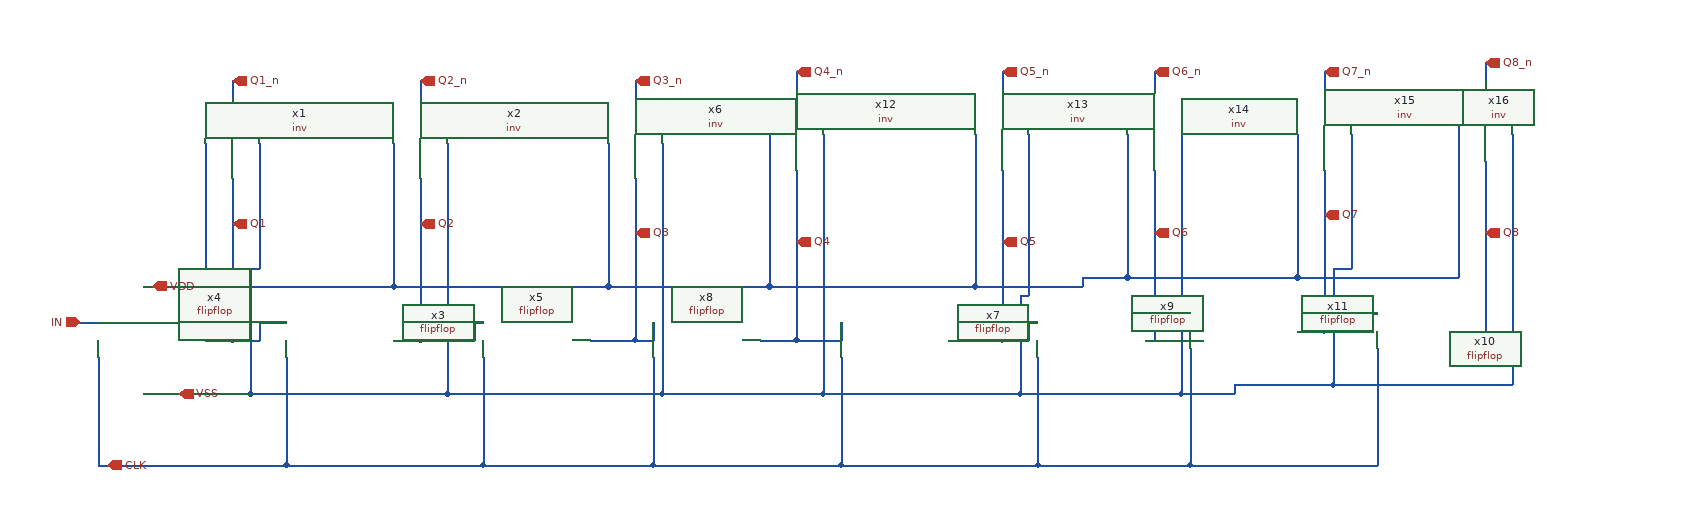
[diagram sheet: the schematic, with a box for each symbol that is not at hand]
v {xschem version=3.4.6 file_version=1.2}
G {}
K {}
V {}
S {}
E {}
N -20 -0 10 -0 {lab=Q1}
N 10 -20 10 -0 {lab=Q1}
N 10 -20 40 -20 {lab=Q1}
N 810 -60 930 -60 {lab=VDD}
N 1040 60 1100 60 {lab=VSS}
N 190 -0 250 0 {lab=Q2}
N 250 -20 250 0 {lab=Q2}
N 250 -20 260 -20 {lab=Q2}
N 840 0 870 0 {lab=Q5}
N 870 -20 870 0 {lab=Q5}
N 870 -20 880 -20 {lab=Q5}
N 430 0 450 0 {lab=Q3}
N 450 -20 450 0 {lab=Q3}
N 1200 -10 1230 -10 {lab=Q7}
N 1230 -30 1230 -10 {lab=Q7}
N 1230 -30 1260 -30 {lab=Q7}
N 40 20 40 140 {lab=CLK}
N 260 20 260 140 {lab=CLK}
N 40 140 260 140 {lab=CLK}
N 450 20 450 140 {lab=CLK}
N 260 140 450 140 {lab=CLK}
N 660 20 660 140 {lab=CLK}
N 450 140 660 140 {lab=CLK}
N 880 20 880 140 {lab=CLK}
N 660 140 880 140 {lab=CLK}
N 1050 10 1050 140 {lab=CLK}
N 880 140 1050 140 {lab=CLK}
N 1260 10 1260 140 {lab=CLK}
N 1050 140 1260 140 {lab=CLK}
N 160 0 190 -0 {lab=Q2}
N 380 0 430 0 {lab=Q3}
N 780 0 840 0 {lab=Q5}
N 1010 -30 1010 0 {lab=Q6}
N 1000 -0 1010 0 {lab=Q6}
N 1170 -10 1200 -10 {lab=Q7}
N -190 -20 -170 -20 {lab=IN}
N -170 140 40 140 {lab=CLK}
N -170 20 -170 140 {lab=CLK}
N -50 0 -20 -0 {lab=Q1}
N 610 -0 660 -0 {lab=Q4}
N 660 -20 660 -0 {lab=Q4}
N 570 0 610 -0 {lab=Q4}
N 1010 -30 1050 -30 {lab=Q6}
N -20 -180 -20 -0 {lab=Q1}
N 190 -180 190 -0 {lab=Q2}
N 430 -180 430 0 {lab=Q3}
N 610 -190 610 -0 {lab=Q4}
N 840 -190 840 0 {lab=Q5}
N 1010 -190 1010 -30 {lab=Q6}
N 1200 -190 1200 -10 {lab=Q7}
N 1380 -200 1380 -10 {lab=Q8}
N -50 -220 -50 -60 {lab=VDD}
N -120 -60 -50 -60 {lab=VDD}
N 10 -220 10 -80 {lab=VSS}
N 0 -80 10 -80 {lab=VSS}
N 0 -80 -0 60 {lab=VSS}
N -120 60 -0 60 {lab=VSS}
N 160 -220 160 -60 {lab=VDD}
N -50 -60 160 -60 {lab=VDD}
N 220 -220 220 60 {lab=VSS}
N -0 60 220 60 {lab=VSS}
N 400 -220 400 -60 {lab=VDD}
N 160 -60 400 -60 {lab=VDD}
N 460 -220 460 60 {lab=VSS}
N 220 60 460 60 {lab=VSS}
N 580 -230 580 -60 {lab=VDD}
N 400 -60 580 -60 {lab=VDD}
N 640 -230 640 60 {lab=VSS}
N 460 60 640 60 {lab=VSS}
N 810 -230 810 -60 {lab=VDD}
N 580 -60 810 -60 {lab=VDD}
N 870 -230 870 -50 {lab=VSS}
N 860 -50 870 -50 {lab=VSS}
N 860 -50 860 60 {lab=VSS}
N 640 60 860 60 {lab=VSS}
N 930 -70 930 -60 {lab=VDD}
N 980 -230 980 -70 {lab=VDD}
N 930 -70 980 -70 {lab=VDD}
N 1100 50 1100 60 {lab=VSS}
N 1040 -230 1040 60 {lab=VSS}
N 860 60 1040 60 {lab=VSS}
N 1170 -230 1170 -70 {lab=VDD}
N 980 -70 1170 -70 {lab=VDD}
N 1210 50 1410 50 {lab=VSS}
N 1350 -240 1350 -70 {lab=VDD}
N 1170 -70 1350 -70 {lab=VDD}
N 1410 -230 1410 50 {lab=VSS}
N -20 -290 -20 -270 {lab=Q1_n}
N 190 -290 190 -270 {lab=Q2_n}
N 430 -290 430 -270 {lab=Q3_n}
N 610 -300 610 -280 {lab=Q4_n}
N 840 -300 840 -280 {lab=Q5_n}
N 1010 -300 1010 -280 {lab=Q6_n}
N 1200 -300 1200 -280 {lab=Q7_n}
N 1380 -310 1380 -290 {lab=Q8_n}
N 1230 -230 1230 -80 {lab=VSS}
N 1210 -80 1230 -80 {lab=VSS}
N 1210 -80 1210 50 {lab=VSS}
N 1100 50 1210 50 {lab=VSS}
C {/home/designer/shared/flipflop.sym} 210 0 0 0 {name=x3}
C {/home/designer/shared/flipflop.sym} 0 0 0 0 {name=x4}
C {/home/designer/shared/flipflop.sym} 430 0 0 0 {name=x5}
C {/home/designer/shared/flipflop.sym} 830 0 0 0 {name=x7}
C {/home/designer/shared/flipflop.sym} 620 0 0 0 {name=x8}
C {/home/designer/shared/flipflop.sym} 1050 0 0 0 {name=x9}
C {/home/designer/shared/flipflop.sym} 1430 -10 0 0 {name=x10}
C {/home/designer/shared/flipflop.sym} 1220 -10 0 0 {name=x11}
C {ipin.sym} -190 -20 0 0 {name=p1 lab=IN}
C {opin.sym} -20 -130 0 0 {name=p2 lab=Q1}
C {iopin.sym} -160 140 0 1 {name=p4 lab=CLK
}
C {iopin.sym} -110 -60 0 1 {name=p3 lab=VDD
}
C {iopin.sym} -80 60 0 1 {name=p6 lab=VSS
}
C {opin.sym} 190 -130 0 0 {name=p5 lab=Q2}
C {opin.sym} 430 -120 0 0 {name=p7 lab=Q3}
C {opin.sym} 610 -110 0 0 {name=p8 lab=Q4}
C {opin.sym} 840 -110 0 0 {name=p9 lab=Q5}
C {opin.sym} 1010 -120 0 0 {name=p10 lab=Q6}
C {opin.sym} 1200 -140 0 0 {name=p11 lab=Q7}
C {opin.sym} 1380 -120 0 0 {name=p12 lab=Q8}
C {/home/designer/shared/inv.sym} 70 -260 3 0 {name=x1}
C {/home/designer/shared/inv.sym} 280 -260 3 0 {name=x2}
C {/home/designer/shared/inv.sym} 520 -260 3 0 {name=x6}
C {/home/designer/shared/inv.sym} 700 -270 3 0 {name=x12}
C {/home/designer/shared/inv.sym} 930 -270 3 0 {name=x13}
C {/home/designer/shared/inv.sym} 1100 -270 3 0 {name=x14}
C {/home/designer/shared/inv.sym} 1290 -270 3 0 {name=x15}
C {/home/designer/shared/inv.sym} 1470 -280 3 0 {name=x16}
C {opin.sym} -20 -290 0 0 {name=p13 lab=Q1_n}
C {opin.sym} 190 -290 0 0 {name=p14 lab=Q2_n}
C {opin.sym} 430 -290 0 0 {name=p15 lab=Q3_n}
C {opin.sym} 610 -300 0 0 {name=p16 lab=Q4_n}
C {opin.sym} 840 -300 0 0 {name=p17 lab=Q5_n}
C {opin.sym} 1010 -300 0 0 {name=p18 lab=Q6_n}
C {opin.sym} 1200 -300 0 0 {name=p19 lab=Q7_n}
C {opin.sym} 1380 -310 0 0 {name=p20 lab=Q8_n}
